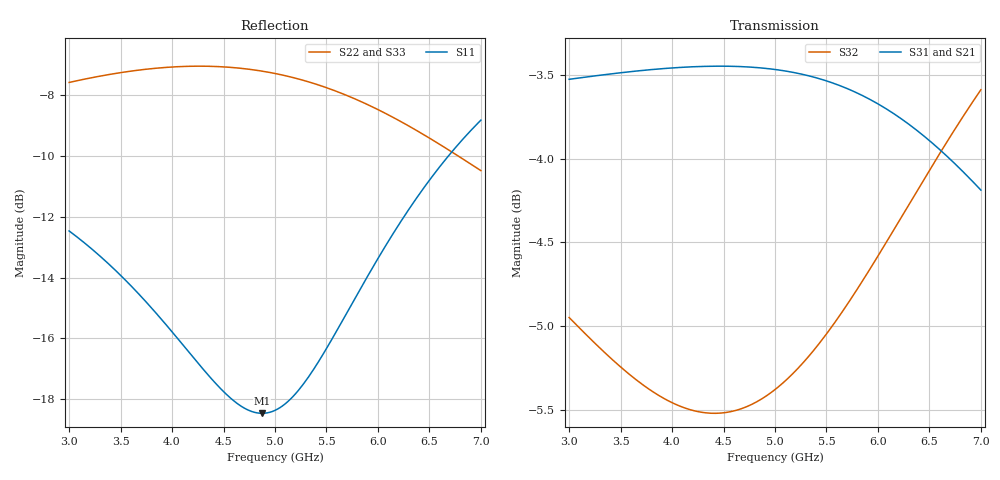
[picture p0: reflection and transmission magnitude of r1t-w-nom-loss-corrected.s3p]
! yapnr Order 0 prediction r1t-w-nom: predictions/references/r1t-w-nom/coarse_dense.s3p, loss-corrected
! substrate W-nom; coupon model OSHPARK-4L-FR408HR; correction: path [('line', 10.75), ('line', 11.0)] (3.0 mm line's Δα)
! |S21|, |S31| (and S12, S13) scaled, phases kept; 50 ohm, e^(+jwt)
# GHz S RI R 50
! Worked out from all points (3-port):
!   161 points, 3 GHz to 7 GHz, reference 50 ohm
!   strongest paths, dB at 3 GHz, 4 GHz, 5 GHz, 6 GHz, 7 GHz:
!     S31: -3.5, -3.5, -3.5, -3.7, -4.2
!     S21: -3.5, -3.5, -3.5, -3.7, -4.2
!     S32: -4.9, -5.5, -5.4, -4.6, -3.6
!   lowest |S11| = -18.5 dB at 4.875 GHz (marker M1), VSWR 1.27, Z = 61.4 + j6.95 ohm
!   |S11| at or under -10 dB: start of sweep to 6.687 GHz
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3  -0.1305 0.199  -0.3223 -0.5843  -0.3223 -0.5843
   -0.3219 -0.5836  0.1932 0.3695  -0.4309 -0.3664
   -0.3219 -0.5836  -0.4309 -0.3664  0.1932 0.3695
3.475  -0.0665 0.1919  -0.5049 -0.4411  -0.5049 -0.4411
       -0.5037 -0.4408  0.3297 0.2791  -0.5146 -0.1871
       -0.5037 -0.4408  -0.5146 -0.1871  0.3297 0.2791
4  0.00464 0.1625  -0.6376 -0.2148  -0.6376 -0.2148
   -0.636 -0.216  0.4262 0.1172  -0.5332 0.0157
   -0.636 -0.216  -0.5332 0.0157  0.4262 0.1172
4.45  0.0613 0.1172  -0.673 0.0121  -0.673 0.0121
      -0.6725 0.00956  0.4402 -0.0465  -0.4986 0.1785
      -0.6725 0.00956  -0.4986 0.1785  0.4402 -0.0465
4.875  0.1056 0.0558  -0.6314 0.228  -0.6314 0.228
       -0.6328 0.2251  0.3904 -0.1922  -0.4296 0.3187
       -0.6328 0.2251  -0.4296 0.3187  0.3904 -0.1922
5  0.1158 0.0343  -0.6052 0.2879  -0.6052 0.2879
   -0.6074 0.2852  0.3653 -0.2294  -0.4027 0.3571
   -0.6074 0.2852  -0.4027 0.3571  0.3653 -0.2294
5.55  0.1373 -0.0776  -0.4237 0.5089  -0.4237 0.5089
      -0.4281 0.5088  0.2154 -0.3441  -0.2457 0.5054
      -0.4281 0.5088  -0.2457 0.5054  0.2154 -0.3441
6.025  0.113 -0.1863  -0.2032 0.6176  -0.2032 0.6176
       -0.2068 0.6211  0.0651 -0.3688  -0.0564 0.5891
       -0.2068 0.6211  -0.0564 0.5891  0.0651 -0.3688
6.525  0.035 -0.2898  0.0495 0.6306  0.0495 0.6306
       0.0494 0.636  -0.0753 -0.3274  0.1864 0.5995
       0.0494 0.636  0.1864 0.5995  -0.0753 -0.3274
7  -0.0834 -0.3518  0.2672 0.5509  0.2672 0.5509
   0.2708 0.555  -0.1706 -0.2453  0.4246 0.5075
   0.2708 0.555  0.4246 0.5075  -0.1706 -0.2453
